VERSION 5.8 ;
BUSBITCHARS "[]" ;
DIVIDERCHAR "/" ;
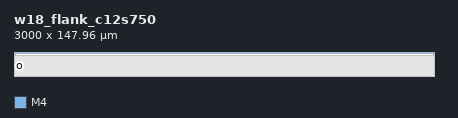
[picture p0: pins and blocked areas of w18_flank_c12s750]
MACRO w18_flank_c12s750
  CLASS BLOCK ;
  FOREIGN w18_flank_c12s750 0 0 ;
  SYMMETRY X Y ;
  SIZE 3000.000 BY 147.960 ;
  PIN o
    DIRECTION OUTPUT ;
    USE SIGNAL ;
    PORT
      LAYER M4 ;
        RECT 0.000 73.968 0.192 73.992 ;
    END
  END o
  OBS
    LAYER M1 ;
      RECT 0.5 0 3000.000 147.960 ;
    LAYER M2 ;
      RECT 0.5 0 3000.000 147.960 ;
    LAYER M3 ;
      RECT 0.5 0 3000.000 147.960 ;
    LAYER M4 ;
      RECT 0.5 0 3000.000 147.960 ;
    LAYER M5 ;
      RECT 0.5 0 3000.000 147.960 ;
    LAYER M6 ;
      RECT 0.5 0 3000.000 147.960 ;
    LAYER M7 ;
      RECT 0.5 0 3000.000 147.960 ;
  END
END w18_flank_c12s750
END LIBRARY
